VERSION 5.7 ;
  NOWIREEXTENSIONATPIN ON ;
  DIVIDERCHAR "/" ;
  BUSBITCHARS "[]" ;
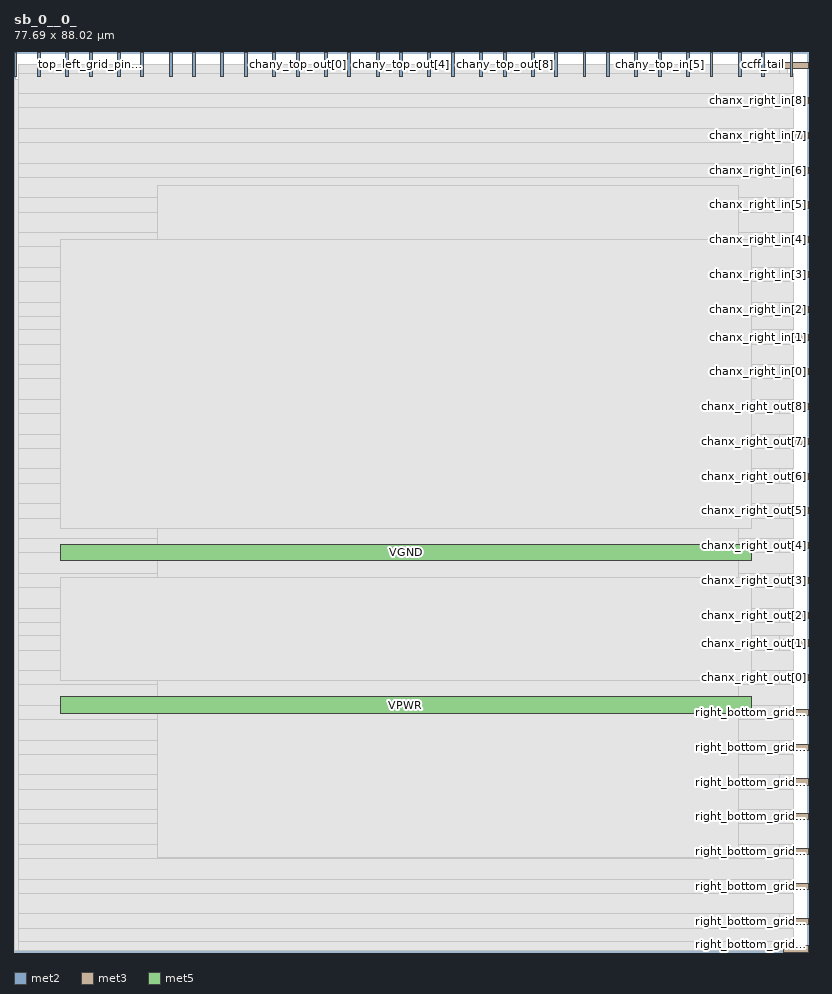
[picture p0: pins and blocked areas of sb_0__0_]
MACRO sb_0__0_
  CLASS BLOCK ;
  FOREIGN sb_0__0_ ;
  ORIGIN 0.000 0.000 ;
  SIZE 77.690 BY 88.020 ;
  PIN ccff_head
    DIRECTION INPUT ;
    PORT
      LAYER met2 ;
        RECT 0.000 85.620 0.280 88.020 ;
    END
  END ccff_head
  PIN ccff_tail
    DIRECTION OUTPUT TRISTATE ;
    PORT
      LAYER met2 ;
        RECT 73.140 85.620 73.420 88.020 ;
    END
  END ccff_tail
  PIN chanx_right_in[0]
    DIRECTION INPUT ;
    PORT
      LAYER met3 ;
        RECT 75.290 56.440 77.690 57.040 ;
    END
  END chanx_right_in[0]
  PIN chanx_right_in[1]
    DIRECTION INPUT ;
    PORT
      LAYER met3 ;
        RECT 75.290 59.840 77.690 60.440 ;
    END
  END chanx_right_in[1]
  PIN chanx_right_in[2]
    DIRECTION INPUT ;
    PORT
      LAYER met3 ;
        RECT 75.290 62.560 77.690 63.160 ;
    END
  END chanx_right_in[2]
  PIN chanx_right_in[3]
    DIRECTION INPUT ;
    PORT
      LAYER met3 ;
        RECT 75.290 65.960 77.690 66.560 ;
    END
  END chanx_right_in[3]
  PIN chanx_right_in[4]
    DIRECTION INPUT ;
    PORT
      LAYER met3 ;
        RECT 75.290 69.360 77.690 69.960 ;
    END
  END chanx_right_in[4]
  PIN chanx_right_in[5]
    DIRECTION INPUT ;
    PORT
      LAYER met3 ;
        RECT 75.290 72.760 77.690 73.360 ;
    END
  END chanx_right_in[5]
  PIN chanx_right_in[6]
    DIRECTION INPUT ;
    PORT
      LAYER met3 ;
        RECT 75.290 76.160 77.690 76.760 ;
    END
  END chanx_right_in[6]
  PIN chanx_right_in[7]
    DIRECTION INPUT ;
    PORT
      LAYER met3 ;
        RECT 75.290 79.560 77.690 80.160 ;
    END
  END chanx_right_in[7]
  PIN chanx_right_in[8]
    DIRECTION INPUT ;
    PORT
      LAYER met3 ;
        RECT 75.290 82.960 77.690 83.560 ;
    END
  END chanx_right_in[8]
  PIN chanx_right_out[0]
    DIRECTION OUTPUT TRISTATE ;
    PORT
      LAYER met3 ;
        RECT 75.290 26.520 77.690 27.120 ;
    END
  END chanx_right_out[0]
  PIN chanx_right_out[1]
    DIRECTION OUTPUT TRISTATE ;
    PORT
      LAYER met3 ;
        RECT 75.290 29.920 77.690 30.520 ;
    END
  END chanx_right_out[1]
  PIN chanx_right_out[2]
    DIRECTION OUTPUT TRISTATE ;
    PORT
      LAYER met3 ;
        RECT 75.290 32.640 77.690 33.240 ;
    END
  END chanx_right_out[2]
  PIN chanx_right_out[3]
    DIRECTION OUTPUT TRISTATE ;
    PORT
      LAYER met3 ;
        RECT 75.290 36.040 77.690 36.640 ;
    END
  END chanx_right_out[3]
  PIN chanx_right_out[4]
    DIRECTION OUTPUT TRISTATE ;
    PORT
      LAYER met3 ;
        RECT 75.290 39.440 77.690 40.040 ;
    END
  END chanx_right_out[4]
  PIN chanx_right_out[5]
    DIRECTION OUTPUT TRISTATE ;
    PORT
      LAYER met3 ;
        RECT 75.290 42.840 77.690 43.440 ;
    END
  END chanx_right_out[5]
  PIN chanx_right_out[6]
    DIRECTION OUTPUT TRISTATE ;
    PORT
      LAYER met3 ;
        RECT 75.290 46.240 77.690 46.840 ;
    END
  END chanx_right_out[6]
  PIN chanx_right_out[7]
    DIRECTION OUTPUT TRISTATE ;
    PORT
      LAYER met3 ;
        RECT 75.290 49.640 77.690 50.240 ;
    END
  END chanx_right_out[7]
  PIN chanx_right_out[8]
    DIRECTION OUTPUT TRISTATE ;
    PORT
      LAYER met3 ;
        RECT 75.290 53.040 77.690 53.640 ;
    END
  END chanx_right_out[8]
  PIN chany_top_in[0]
    DIRECTION INPUT ;
    PORT
      LAYER met2 ;
        RECT 50.600 85.620 50.880 88.020 ;
    END
  END chany_top_in[0]
  PIN chany_top_in[1]
    DIRECTION INPUT ;
    PORT
      LAYER met2 ;
        RECT 52.900 85.620 53.180 88.020 ;
    END
  END chany_top_in[1]
  PIN chany_top_in[2]
    DIRECTION INPUT ;
    PORT
      LAYER met2 ;
        RECT 55.660 85.620 55.940 88.020 ;
    END
  END chany_top_in[2]
  PIN chany_top_in[3]
    DIRECTION INPUT ;
    PORT
      LAYER met2 ;
        RECT 57.960 85.620 58.240 88.020 ;
    END
  END chany_top_in[3]
  PIN chany_top_in[4]
    DIRECTION INPUT ;
    PORT
      LAYER met2 ;
        RECT 60.720 85.620 61.000 88.020 ;
    END
  END chany_top_in[4]
  PIN chany_top_in[5]
    DIRECTION INPUT ;
    PORT
      LAYER met2 ;
        RECT 63.020 85.620 63.300 88.020 ;
    END
  END chany_top_in[5]
  PIN chany_top_in[6]
    DIRECTION INPUT ;
    PORT
      LAYER met2 ;
        RECT 65.780 85.620 66.060 88.020 ;
    END
  END chany_top_in[6]
  PIN chany_top_in[7]
    DIRECTION INPUT ;
    PORT
      LAYER met2 ;
        RECT 68.080 85.620 68.360 88.020 ;
    END
  END chany_top_in[7]
  PIN chany_top_in[8]
    DIRECTION INPUT ;
    PORT
      LAYER met2 ;
        RECT 70.840 85.620 71.120 88.020 ;
    END
  END chany_top_in[8]
  PIN chany_top_out[0]
    DIRECTION OUTPUT TRISTATE ;
    PORT
      LAYER met2 ;
        RECT 27.600 85.620 27.880 88.020 ;
    END
  END chany_top_out[0]
  PIN chany_top_out[1]
    DIRECTION OUTPUT TRISTATE ;
    PORT
      LAYER met2 ;
        RECT 30.360 85.620 30.640 88.020 ;
    END
  END chany_top_out[1]
  PIN chany_top_out[2]
    DIRECTION OUTPUT TRISTATE ;
    PORT
      LAYER met2 ;
        RECT 32.660 85.620 32.940 88.020 ;
    END
  END chany_top_out[2]
  PIN chany_top_out[3]
    DIRECTION OUTPUT TRISTATE ;
    PORT
      LAYER met2 ;
        RECT 35.420 85.620 35.700 88.020 ;
    END
  END chany_top_out[3]
  PIN chany_top_out[4]
    DIRECTION OUTPUT TRISTATE ;
    PORT
      LAYER met2 ;
        RECT 37.720 85.620 38.000 88.020 ;
    END
  END chany_top_out[4]
  PIN chany_top_out[5]
    DIRECTION OUTPUT TRISTATE ;
    PORT
      LAYER met2 ;
        RECT 40.480 85.620 40.760 88.020 ;
    END
  END chany_top_out[5]
  PIN chany_top_out[6]
    DIRECTION OUTPUT TRISTATE ;
    PORT
      LAYER met2 ;
        RECT 42.780 85.620 43.060 88.020 ;
    END
  END chany_top_out[6]
  PIN chany_top_out[7]
    DIRECTION OUTPUT TRISTATE ;
    PORT
      LAYER met2 ;
        RECT 45.540 85.620 45.820 88.020 ;
    END
  END chany_top_out[7]
  PIN chany_top_out[8]
    DIRECTION OUTPUT TRISTATE ;
    PORT
      LAYER met2 ;
        RECT 47.840 85.620 48.120 88.020 ;
    END
  END chany_top_out[8]
  PIN pReset
    DIRECTION INPUT ;
    PORT
      LAYER met2 ;
        RECT 22.540 85.620 22.820 88.020 ;
    END
  END pReset
  PIN prog_clk
    DIRECTION INPUT ;
    PORT
      LAYER met2 ;
        RECT 25.300 85.620 25.580 88.020 ;
    END
  END prog_clk
  PIN right_bottom_grid_pin_11_
    DIRECTION INPUT ;
    PORT
      LAYER met3 ;
        RECT 75.290 16.320 77.690 16.920 ;
    END
  END right_bottom_grid_pin_11_
  PIN right_bottom_grid_pin_13_
    DIRECTION INPUT ;
    PORT
      LAYER met3 ;
        RECT 75.290 19.720 77.690 20.320 ;
    END
  END right_bottom_grid_pin_13_
  PIN right_bottom_grid_pin_15_
    DIRECTION INPUT ;
    PORT
      LAYER met3 ;
        RECT 75.290 23.120 77.690 23.720 ;
    END
  END right_bottom_grid_pin_15_
  PIN right_bottom_grid_pin_1_
    DIRECTION INPUT ;
    PORT
      LAYER met3 ;
        RECT 75.290 0.000 77.690 0.600 ;
    END
  END right_bottom_grid_pin_1_
  PIN right_bottom_grid_pin_3_
    DIRECTION INPUT ;
    PORT
      LAYER met3 ;
        RECT 75.290 2.720 77.690 3.320 ;
    END
  END right_bottom_grid_pin_3_
  PIN right_bottom_grid_pin_5_
    DIRECTION INPUT ;
    PORT
      LAYER met3 ;
        RECT 75.290 6.120 77.690 6.720 ;
    END
  END right_bottom_grid_pin_5_
  PIN right_bottom_grid_pin_7_
    DIRECTION INPUT ;
    PORT
      LAYER met3 ;
        RECT 75.290 9.520 77.690 10.120 ;
    END
  END right_bottom_grid_pin_7_
  PIN right_bottom_grid_pin_9_
    DIRECTION INPUT ;
    PORT
      LAYER met3 ;
        RECT 75.290 12.920 77.690 13.520 ;
    END
  END right_bottom_grid_pin_9_
  PIN right_top_grid_pin_10_
    DIRECTION INPUT ;
    PORT
      LAYER met3 ;
        RECT 75.290 86.360 77.690 86.960 ;
    END
  END right_top_grid_pin_10_
  PIN top_left_grid_pin_11_
    DIRECTION INPUT ;
    PORT
      LAYER met2 ;
        RECT 15.180 85.620 15.460 88.020 ;
    END
  END top_left_grid_pin_11_
  PIN top_left_grid_pin_13_
    DIRECTION INPUT ;
    PORT
      LAYER met2 ;
        RECT 17.480 85.620 17.760 88.020 ;
    END
  END top_left_grid_pin_13_
  PIN top_left_grid_pin_15_
    DIRECTION INPUT ;
    PORT
      LAYER met2 ;
        RECT 20.240 85.620 20.520 88.020 ;
    END
  END top_left_grid_pin_15_
  PIN top_left_grid_pin_1_
    DIRECTION INPUT ;
    PORT
      LAYER met2 ;
        RECT 2.300 85.620 2.580 88.020 ;
    END
  END top_left_grid_pin_1_
  PIN top_left_grid_pin_3_
    DIRECTION INPUT ;
    PORT
      LAYER met2 ;
        RECT 5.060 85.620 5.340 88.020 ;
    END
  END top_left_grid_pin_3_
  PIN top_left_grid_pin_5_
    DIRECTION INPUT ;
    PORT
      LAYER met2 ;
        RECT 7.360 85.620 7.640 88.020 ;
    END
  END top_left_grid_pin_5_
  PIN top_left_grid_pin_7_
    DIRECTION INPUT ;
    PORT
      LAYER met2 ;
        RECT 10.120 85.620 10.400 88.020 ;
    END
  END top_left_grid_pin_7_
  PIN top_left_grid_pin_9_
    DIRECTION INPUT ;
    PORT
      LAYER met2 ;
        RECT 12.420 85.620 12.700 88.020 ;
    END
  END top_left_grid_pin_9_
  PIN top_right_grid_pin_11_
    DIRECTION INPUT ;
    PORT
      LAYER met2 ;
        RECT 75.900 85.620 76.180 88.020 ;
    END
  END top_right_grid_pin_11_
  PIN VPWR
    DIRECTION INPUT ;
    USE POWER ;
    PORT
      LAYER met5 ;
        RECT 4.510 23.345 72.130 24.945 ;
    END
  END VPWR
  PIN VGND
    DIRECTION INPUT ;
    USE GROUND ;
    PORT
      LAYER met5 ;
        RECT 4.510 38.245 72.130 39.845 ;
    END
  END VGND
  OBS
      LAYER li1 ;
        RECT 4.510 9.395 72.130 74.845 ;
      LAYER met1 ;
        RECT 2.280 9.240 72.130 76.420 ;
      LAYER met2 ;
        RECT 0.560 85.340 2.020 86.845 ;
        RECT 2.860 85.340 4.780 86.845 ;
        RECT 5.620 85.340 7.080 86.845 ;
        RECT 7.920 85.340 9.840 86.845 ;
        RECT 10.680 85.340 12.140 86.845 ;
        RECT 12.980 85.340 14.900 86.845 ;
        RECT 15.740 85.340 17.200 86.845 ;
        RECT 18.040 85.340 19.960 86.845 ;
        RECT 20.800 85.340 22.260 86.845 ;
        RECT 23.100 85.340 25.020 86.845 ;
        RECT 25.860 85.340 27.320 86.845 ;
        RECT 28.160 85.340 30.080 86.845 ;
        RECT 30.920 85.340 32.380 86.845 ;
        RECT 33.220 85.340 35.140 86.845 ;
        RECT 35.980 85.340 37.440 86.845 ;
        RECT 38.280 85.340 40.200 86.845 ;
        RECT 41.040 85.340 42.500 86.845 ;
        RECT 43.340 85.340 45.260 86.845 ;
        RECT 46.100 85.340 47.560 86.845 ;
        RECT 48.400 85.340 50.320 86.845 ;
        RECT 51.160 85.340 52.620 86.845 ;
        RECT 53.460 85.340 55.380 86.845 ;
        RECT 56.220 85.340 57.680 86.845 ;
        RECT 58.520 85.340 60.440 86.845 ;
        RECT 61.280 85.340 62.740 86.845 ;
        RECT 63.580 85.340 65.500 86.845 ;
        RECT 66.340 85.340 67.800 86.845 ;
        RECT 68.640 85.340 70.560 86.845 ;
        RECT 71.400 85.340 72.860 86.845 ;
        RECT 73.700 85.340 75.620 86.845 ;
        RECT 0.070 0.115 76.180 85.340 ;
      LAYER met3 ;
        RECT 0.435 85.960 74.890 86.825 ;
        RECT 0.435 83.960 76.205 85.960 ;
        RECT 0.435 82.560 74.890 83.960 ;
        RECT 0.435 80.560 76.205 82.560 ;
        RECT 0.435 79.160 74.890 80.560 ;
        RECT 0.435 77.160 76.205 79.160 ;
        RECT 0.435 75.760 74.890 77.160 ;
        RECT 0.435 73.760 76.205 75.760 ;
        RECT 0.435 72.360 74.890 73.760 ;
        RECT 0.435 70.360 76.205 72.360 ;
        RECT 0.435 68.960 74.890 70.360 ;
        RECT 0.435 66.960 76.205 68.960 ;
        RECT 0.435 65.560 74.890 66.960 ;
        RECT 0.435 63.560 76.205 65.560 ;
        RECT 0.435 62.160 74.890 63.560 ;
        RECT 0.435 60.840 76.205 62.160 ;
        RECT 0.435 59.440 74.890 60.840 ;
        RECT 0.435 57.440 76.205 59.440 ;
        RECT 0.435 56.040 74.890 57.440 ;
        RECT 0.435 54.040 76.205 56.040 ;
        RECT 0.435 52.640 74.890 54.040 ;
        RECT 0.435 50.640 76.205 52.640 ;
        RECT 0.435 49.240 74.890 50.640 ;
        RECT 0.435 47.240 76.205 49.240 ;
        RECT 0.435 45.840 74.890 47.240 ;
        RECT 0.435 43.840 76.205 45.840 ;
        RECT 0.435 42.440 74.890 43.840 ;
        RECT 0.435 40.440 76.205 42.440 ;
        RECT 0.435 39.040 74.890 40.440 ;
        RECT 0.435 37.040 76.205 39.040 ;
        RECT 0.435 35.640 74.890 37.040 ;
        RECT 0.435 33.640 76.205 35.640 ;
        RECT 0.435 32.240 74.890 33.640 ;
        RECT 0.435 30.920 76.205 32.240 ;
        RECT 0.435 29.520 74.890 30.920 ;
        RECT 0.435 27.520 76.205 29.520 ;
        RECT 0.435 26.120 74.890 27.520 ;
        RECT 0.435 24.120 76.205 26.120 ;
        RECT 0.435 22.720 74.890 24.120 ;
        RECT 0.435 20.720 76.205 22.720 ;
        RECT 0.435 19.320 74.890 20.720 ;
        RECT 0.435 17.320 76.205 19.320 ;
        RECT 0.435 15.920 74.890 17.320 ;
        RECT 0.435 13.920 76.205 15.920 ;
        RECT 0.435 12.520 74.890 13.920 ;
        RECT 0.435 10.520 76.205 12.520 ;
        RECT 0.435 9.120 74.890 10.520 ;
        RECT 0.435 7.120 76.205 9.120 ;
        RECT 0.435 5.720 74.890 7.120 ;
        RECT 0.435 3.720 76.205 5.720 ;
        RECT 0.435 2.320 74.890 3.720 ;
        RECT 0.435 1.000 76.205 2.320 ;
        RECT 0.435 0.135 74.890 1.000 ;
      LAYER met4 ;
        RECT 14.005 9.240 70.890 75.000 ;
      LAYER met5 ;
        RECT 4.510 41.445 72.130 69.650 ;
        RECT 4.510 26.545 72.130 36.645 ;
  END
END sb_0__0_
END LIBRARY

